(* Logix 5000 AddOnInstructionDefinition export Banner_R95C_4B4UI_Param_v4; software revision 33.00; part 2 of 2 *)
(* tags used below, declared in another part *)
   R95C : Banner_R95C_4B4UI_v4;
   Port_Data : Banner_IOL_Port_v4;
   Port : INT;   // Port Number that device is plugged into.
   Local_Control : DINT;
   Command_Being_Processed : BOOL;
   Update_Archive : BOOL;
   Index_Write_Inprocess : DINT;
   Index_Write_Control : DINT;
   Inprocess_Index : DINT;
   Index2 : DINT;
   Index3 : DINT;
(* Banner_R95C_4B4UI_Param_v4, continued *)

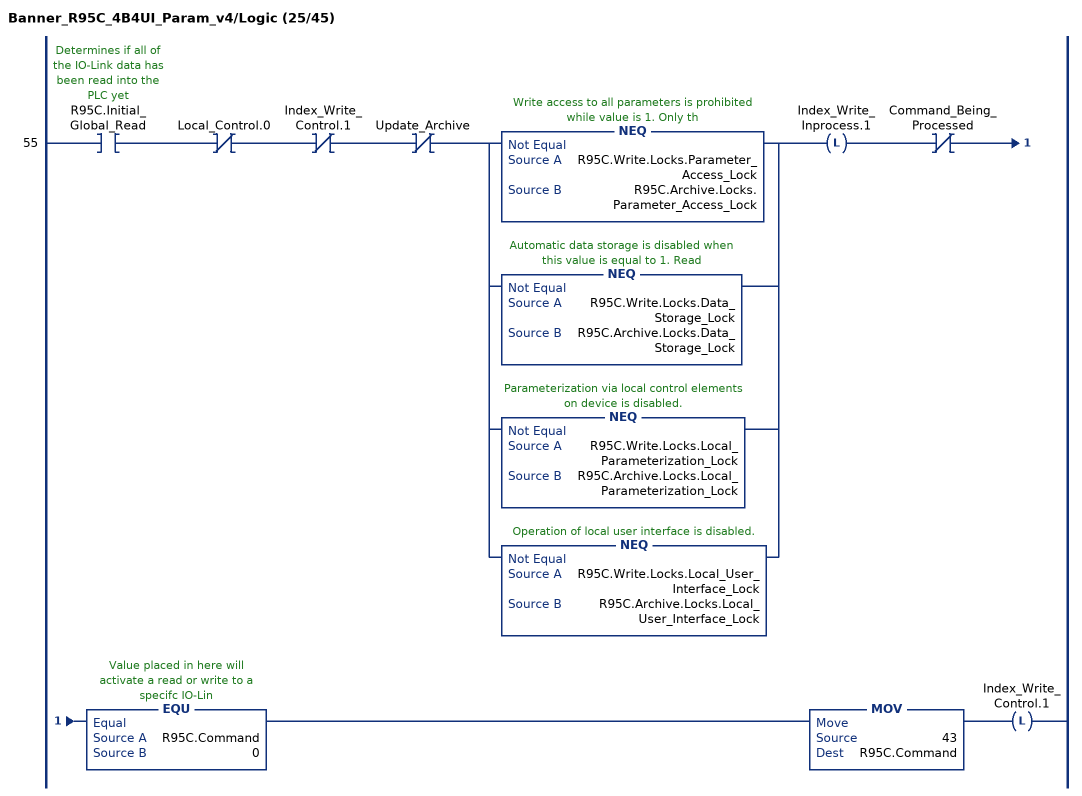
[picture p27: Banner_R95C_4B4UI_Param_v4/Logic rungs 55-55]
   55: XIC(R95C.Initial_Global_Read)XIO(Local_Control.0)XIO(Index_Write_Control.1)XIO(Update_Archive)[NEQ(R95C.Write.Locks.Parameter_Access_Lock,R95C.Archive.Locks.Parameter_Access_Lock) ,NEQ(R95C.Write.Locks.Data_Storage_Lock,R95C.Archive.Locks.Data_Storage_Lock) ,NEQ(R95C.Write.Locks.Local_Parameterization_Lock,R95C.Archive.Locks.Local_Parameterization_Lock) ,NEQ(R95C.Write.Locks.Local_User_Interface_Lock,R95C.Archive.Locks.Local_User_Interface_Lock) ]OTL(Index_Write_Inprocess.1)XIO(Command_Being_Processed)EQU(R95C.Command,0)MOV(43,R95C.Command)OTL(Index_Write_Control.1);
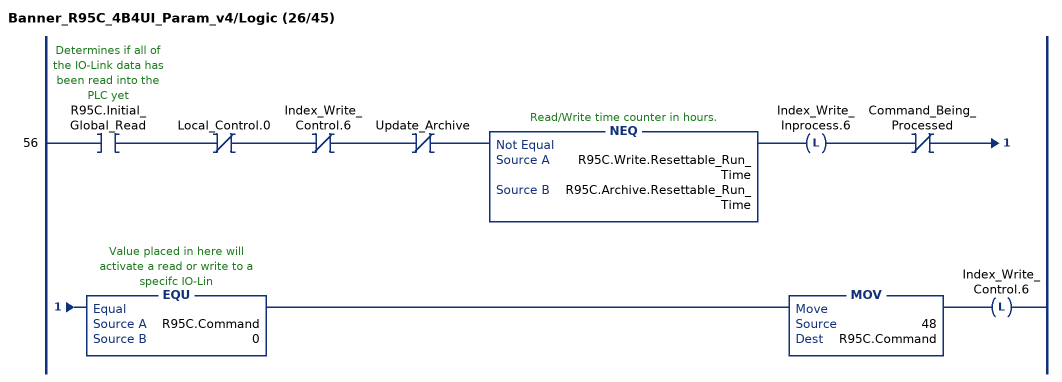
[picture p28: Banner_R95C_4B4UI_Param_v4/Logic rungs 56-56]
   56: XIC(R95C.Initial_Global_Read)XIO(Local_Control.0)XIO(Index_Write_Control.6)XIO(Update_Archive)NEQ(R95C.Write.Resettable_Run_Time,R95C.Archive.Resettable_Run_Time)OTL(Index_Write_Inprocess.6)XIO(Command_Being_Processed)EQU(R95C.Command,0)MOV(48,R95C.Command)OTL(Index_Write_Control.6);
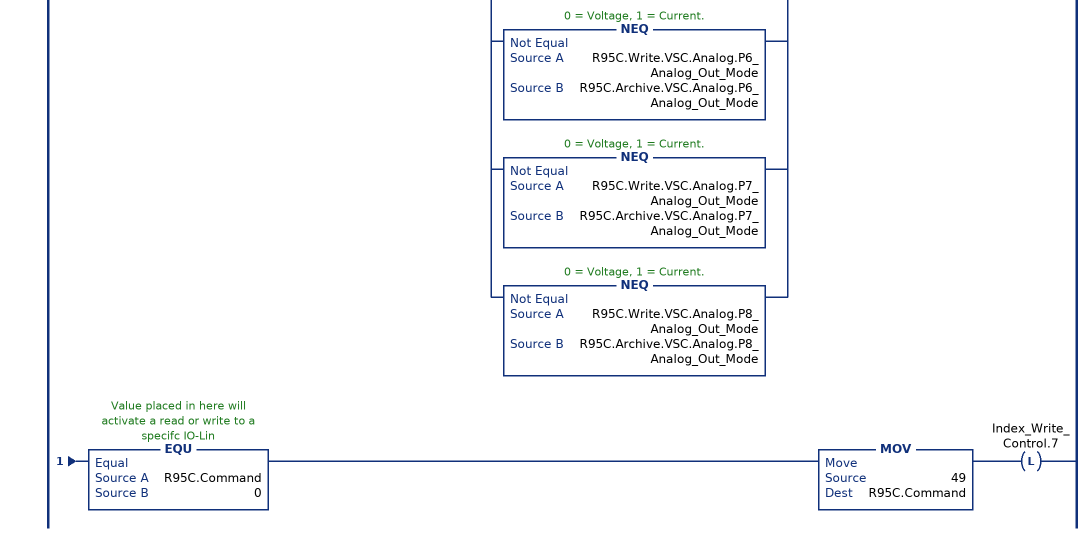
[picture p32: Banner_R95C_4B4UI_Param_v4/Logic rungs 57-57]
   57: XIC(R95C.Initial_Global_Read)XIO(Local_Control.0)XIO(Index_Write_Control.7)XIO(Update_Archive)[NEQ(R95C.Write.VSC.PDI_Config,R95C.Archive.VSC.PDI_Config) ,NEQ(R95C.Write.VSC.Measure1.Channel_Selection,R95C.Archive.VSC.Measure1.Channel_Selection) ,NEQ(R95C.Write.VSC.Measure1.Port_Selection,R95C.Archive.VSC.Measure1.Port_Selection) ,NEQ(R95C.Write.VSC.Measure1.Metric_Selection,R95C.Archive.VSC.Measure1.Metric_Selection) ,NEQ(R95C.Write.VSC.Measure2.Channel_Selection,R95C.Archive.VSC.Measure2.Channel_Selection) ,NEQ(R95C.Write.VSC.Measure2.Port_Selection,R95C.Archive.VSC.Measure2.Port_Selection) ,NEQ(R95C.Write.VSC.Measure2.Metric_Selection,R95C.Archive.VSC.Measure2.Metric_Selection) ,NEQ(R95C.Write.VSC.Measure3.Channel_Selection,R95C.Archive.VSC.Measure3.Channel_Selection) ,NEQ(R95C.Write.VSC.Measure3.Port_Selection,R95C.Archive.VSC.Measure3.Port_Selection) ,NEQ(R95C.Write.VSC.Measure3.Metric_Selection,R95C.Archive.VSC.Measure3.Metric_Selection) ,NEQ(R95C.Write.VSC.Measure4.Channel_Selection,R95C.Archive.VSC.Measure4.Channel_Selection) ,NEQ(R95C.Write.VSC.Measure4.Port_Selection,R95C.Archive.VSC.Measure4.Port_Selection) ,NEQ(R95C.Write.VSC.Measure4.Metric_Selection,R95C.Archive.VSC.Measure4.Metric_Selection) ,NEQ(R95C.Write.VSC.POVR.PDO5_OVD,R95C.Archive.VSC.POVR.PDO5_OVD) ,NEQ(R95C.Write.VSC.POVR.PDO6_OVD,R95C.Archive.VSC.POVR.PDO6_OVD) ,NEQ(R95C.Write.VSC.POVR.PDO7_OVD,R95C.Archive.VSC.POVR.PDO7_OVD) ,NEQ(R95C.Write.VSC.POVR.PDO8_OVD,R95C.Archive.VSC.POVR.PDO8_OVD) ,NEQ(R95C.Write.VSC.IOL_Filter_Time,R95C.Archive.VSC.IOL_Filter_Time) ,NEQ(R95C.Write.VSC.Analog.P5_Mode_Analog_In,R95C.Archive.VSC.Analog.P5_Mode_Analog_In) ,NEQ(R95C.Write.VSC.Analog.P6_Mode_Analog_In,R95C.Archive.VSC.Analog.P6_Mode_Analog_In) ,NEQ(R95C.Write.VSC.Analog.P7_Mode_Analog_In,R95C.Archive.VSC.Analog.P7_Mode_Analog_In) ,NEQ(R95C.Write.VSC.Analog.P8_Mode_Analog_In,R95C.Archive.VSC.Analog.P8_Mode_Analog_In) ,NEQ(R95C.Write.VSC.Analog.P5_Analog_Out_Mode,R95C.Archive.VSC.Analog.P5_Analog_Out_Mode) ,NEQ(R95C.Write.VSC.Analog.P6_Analog_Out_Mode,R95C.Archive.VSC.Analog.P6_Analog_Out_Mode) ,NEQ(R95C.Write.VSC.Analog.P7_Analog_Out_Mode,R95C.Archive.VSC.Analog.P7_Analog_Out_Mode) ,NEQ(R95C.Write.VSC.Analog.P8_Analog_Out_Mode,R95C.Archive.VSC.Analog.P8_Analog_Out_Mode) ]OTL(Index_Write_Inprocess.7)XIO(Command_Being_Processed)EQU(R95C.Command,0)MOV(49,R95C.Command)OTL(Index_Write_Control.7);
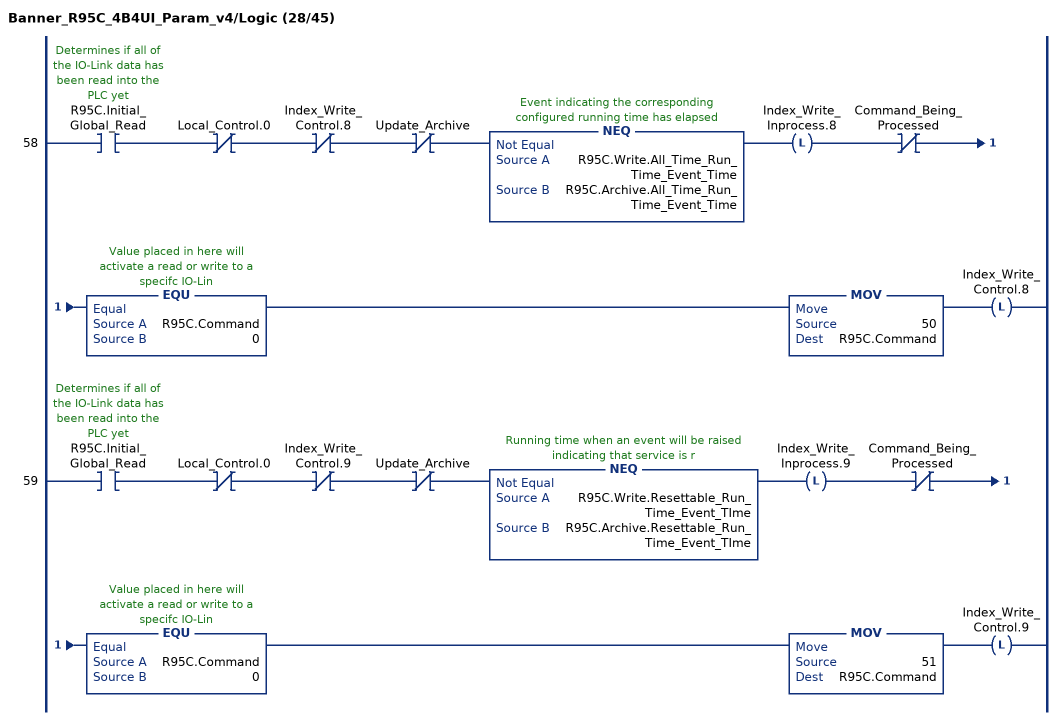
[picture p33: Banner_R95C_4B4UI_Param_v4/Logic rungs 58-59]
   58: XIC(R95C.Initial_Global_Read)XIO(Local_Control.0)XIO(Index_Write_Control.8)XIO(Update_Archive)NEQ(R95C.Write.All_Time_Run_Time_Event_Time,R95C.Archive.All_Time_Run_Time_Event_Time)OTL(Index_Write_Inprocess.8)XIO(Command_Being_Processed)EQU(R95C.Command,0)MOV(50,R95C.Command)OTL(Index_Write_Control.8);
   59: XIC(R95C.Initial_Global_Read)XIO(Local_Control.0)XIO(Index_Write_Control.9)XIO(Update_Archive)NEQ(R95C.Write.Resettable_Run_Time_Event_TIme,R95C.Archive.Resettable_Run_Time_Event_TIme)OTL(Index_Write_Inprocess.9)XIO(Command_Being_Processed)EQU(R95C.Command,0)MOV(51,R95C.Command)OTL(Index_Write_Control.9);
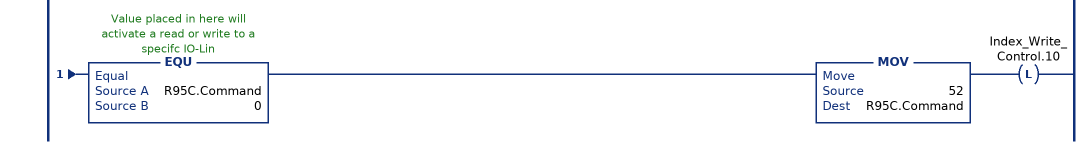
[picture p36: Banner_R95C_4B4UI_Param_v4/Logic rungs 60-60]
   60: XIC(R95C.Initial_Global_Read)XIO(Local_Control.0)XIO(Index_Write_Control.10)XIO(Update_Archive)[NEQ(R95C.Write.SMR.P4_D2_Reset_Count,R95C.Archive.SMR.P4_D2_Reset_Count) ,NEQ(R95C.Write.SMR.P4_D1_Reset_Count,R95C.Archive.SMR.P4_D1_Reset_Count) ,NEQ(R95C.Write.SMR.P3_D2_Reset_Count,R95C.Archive.SMR.P3_D2_Reset_Count) ,NEQ(R95C.Write.SMR.P3_D1_Reset_Count,R95C.Archive.SMR.P3_D1_Reset_Count) ,NEQ(R95C.Write.SMR.P2_D2_Reset_Count,R95C.Archive.SMR.P2_D2_Reset_Count) ,NEQ(R95C.Write.SMR.P2_D1_Reset_Count,R95C.Archive.SMR.P2_D1_Reset_Count) ,NEQ(R95C.Write.SMR.P1_D2_Reset_Count,R95C.Archive.SMR.P1_D2_Reset_Count) ,NEQ(R95C.Write.SMR.P1_D1_Reset_Count,R95C.Archive.SMR.P1_D1_Reset_Count) ,NEQ(R95C.Write.SMR.P1_Discrete1,R95C.Archive.SMR.P1_Discrete1) ,NEQ(R95C.Write.SMR.P1_Discrete2,R95C.Archive.SMR.P1_Discrete2) ,NEQ(R95C.Write.SMR.P2_Discrete1,R95C.Archive.SMR.P2_Discrete1) ,NEQ(R95C.Write.SMR.P2_Discrete2,R95C.Archive.SMR.P2_Discrete2) ,NEQ(R95C.Write.SMR.P3_Discrete1,R95C.Archive.SMR.P3_Discrete1) ,NEQ(R95C.Write.SMR.P3_Discrete2,R95C.Archive.SMR.P3_Discrete2) ,NEQ(R95C.Write.SMR.P4_Discrete1,R95C.Archive.SMR.P4_Discrete1) ,NEQ(R95C.Write.SMR.P4_Discrete2,R95C.Archive.SMR.P4_Discrete2) ]OTL(Index_Write_Inprocess.10)XIO(Command_Being_Processed)EQU(R95C.Command,0)MOV(52,R95C.Command)OTL(Index_Write_Control.10);
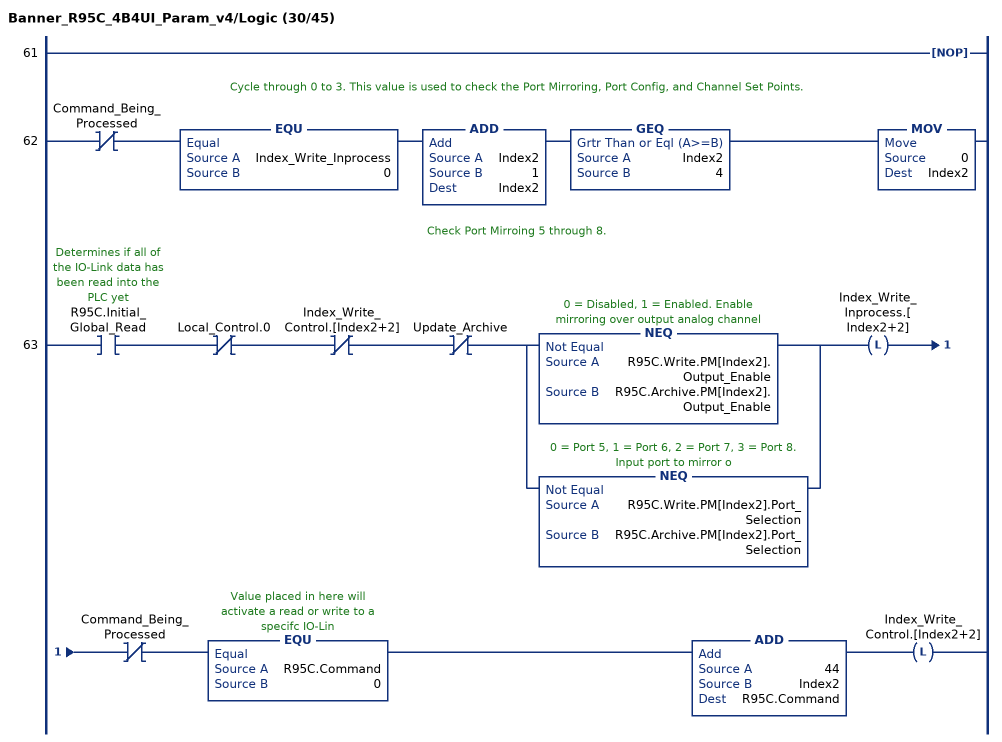
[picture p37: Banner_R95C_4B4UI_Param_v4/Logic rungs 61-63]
   61: NOP();
   // Cycle through 0 to 3. This value is used to check the Port Mirroring, Port Config, and Channel Set Points.
   62: XIO(Command_Being_Processed)EQU(Index_Write_Inprocess,0)ADD(Index2,1,Index2)GEQ(Index2,4)MOV(0,Index2);
   // Check Port Mirroing 5 through 8.
   63: XIC(R95C.Initial_Global_Read)XIO(Local_Control.0)XIO(Index_Write_Control.[Index2+2])XIO(Update_Archive)[NEQ(R95C.Write.PM[Index2].Output_Enable,R95C.Archive.PM[Index2].Output_Enable) ,NEQ(R95C.Write.PM[Index2].Port_Selection,R95C.Archive.PM[Index2].Port_Selection) ]OTL(Index_Write_Inprocess.[Index2+2])XIO(Command_Being_Processed)EQU(R95C.Command,0)ADD(44,Index2,R95C.Command)OTL(Index_Write_Control.[Index2+2]);
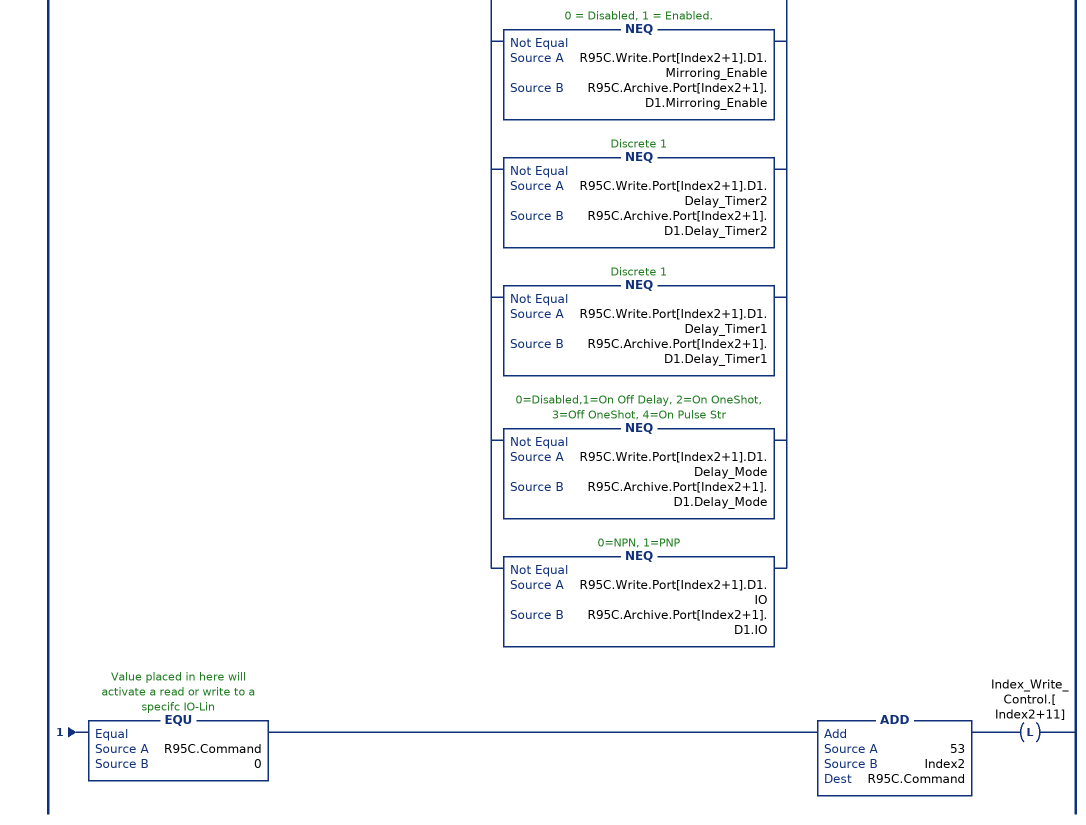
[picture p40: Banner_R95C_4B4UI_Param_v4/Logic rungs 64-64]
   // Check Port Confiuration 1 through 4.
   64: XIC(R95C.Initial_Global_Read)XIO(Local_Control.0)XIO(Index_Write_Control.[Index2+11])XIO(Update_Archive)[NEQ(R95C.Write.Port[Index2+1].D2.PFM_Far_Freq,R95C.Archive.Port[Index2+1].D2.PFM_Far_Freq) ,NEQ(R95C.Write.Port[Index2+1].D2.PFM_Near_Freq,R95C.Archive.Port[Index2+1].D2.PFM_Near_Freq) ,NEQ(R95C.Write.Port[Index2+1].D2.Mirroring_Inversion,R95C.Archive.Port[Index2+1].D2.Mirroring_Inversion) ,NEQ(R95C.Write.Port[Index2+1].D2.Mirroring_Channel_Selection,R95C.Archive.Port[Index2+1].D2.Mirroring_Channel_Selection) ,NEQ(R95C.Write.Port[Index2+1].D2.Mirroring_Port_Selection,R95C.Archive.Port[Index2+1].D2.Mirroring_Port_Selection) ,NEQ(R95C.Write.Port[Index2+1].D2.Mirroring_Enable,R95C.Archive.Port[Index2+1].D2.Mirroring_Enable) ,NEQ(R95C.Write.Port[Index2+1].D2.Delay_Timer2,R95C.Archive.Port[Index2+1].D2.Delay_Timer2) ,NEQ(R95C.Write.Port[Index2+1].D2.Delay_Timer1,R95C.Archive.Port[Index2+1].D2.Delay_Timer1) ,NEQ(R95C.Write.Port[Index2+1].D2.Delay_Mode,R95C.Archive.Port[Index2+1].D2.Delay_Mode) ,NEQ(R95C.Write.Port[Index2+1].D2.IO,R95C.Archive.Port[Index2+1].D2.IO) ,NEQ(R95C.Write.Port[Index2+1].D1.PFM_Far_Freq,R95C.Archive.Port[Index2+1].D1.PFM_Far_Freq) ,NEQ(R95C.Write.Port[Index2+1].D1.PFM_Near_Freq,R95C.Archive.Port[Index2+1].D1.PFM_Near_Freq) ,NEQ(R95C.Write.Port[Index2+1].D1.Mirroring_Inversion,R95C.Archive.Port[Index2+1].D1.Mirroring_Inversion) ,NEQ(R95C.Write.Port[Index2+1].D1.Mirroring_Channel_Selection,R95C.Archive.Port[Index2+1].D1.Mirroring_Channel_Selection) ,NEQ(R95C.Write.Port[Index2+1].D1.Mirroring_Port_Selection,R95C.Archive.Port[Index2+1].D1.Mirroring_Port_Selection) ,NEQ(R95C.Write.Port[Index2+1].D1.Mirroring_Enable,R95C.Archive.Port[Index2+1].D1.Mirroring_Enable) ,NEQ(R95C.Write.Port[Index2+1].D1.Delay_Timer2,R95C.Archive.Port[Index2+1].D1.Delay_Timer2) ,NEQ(R95C.Write.Port[Index2+1].D1.Delay_Timer1,R95C.Archive.Port[Index2+1].D1.Delay_Timer1) ,NEQ(R95C.Write.Port[Index2+1].D1.Delay_Mode,R95C.Archive.Port[Index2+1].D1.Delay_Mode) ,NEQ(R95C.Write.Port[Index2+1].D1.IO,R95C.Archive.Port[Index2+1].D1.IO) ]OTL(Index_Write_Inprocess.[Index2+11])XIO(Command_Being_Processed)EQU(R95C.Command,0)ADD(53,Index2,R95C.Command)OTL(Index_Write_Control.[Index2+11]);
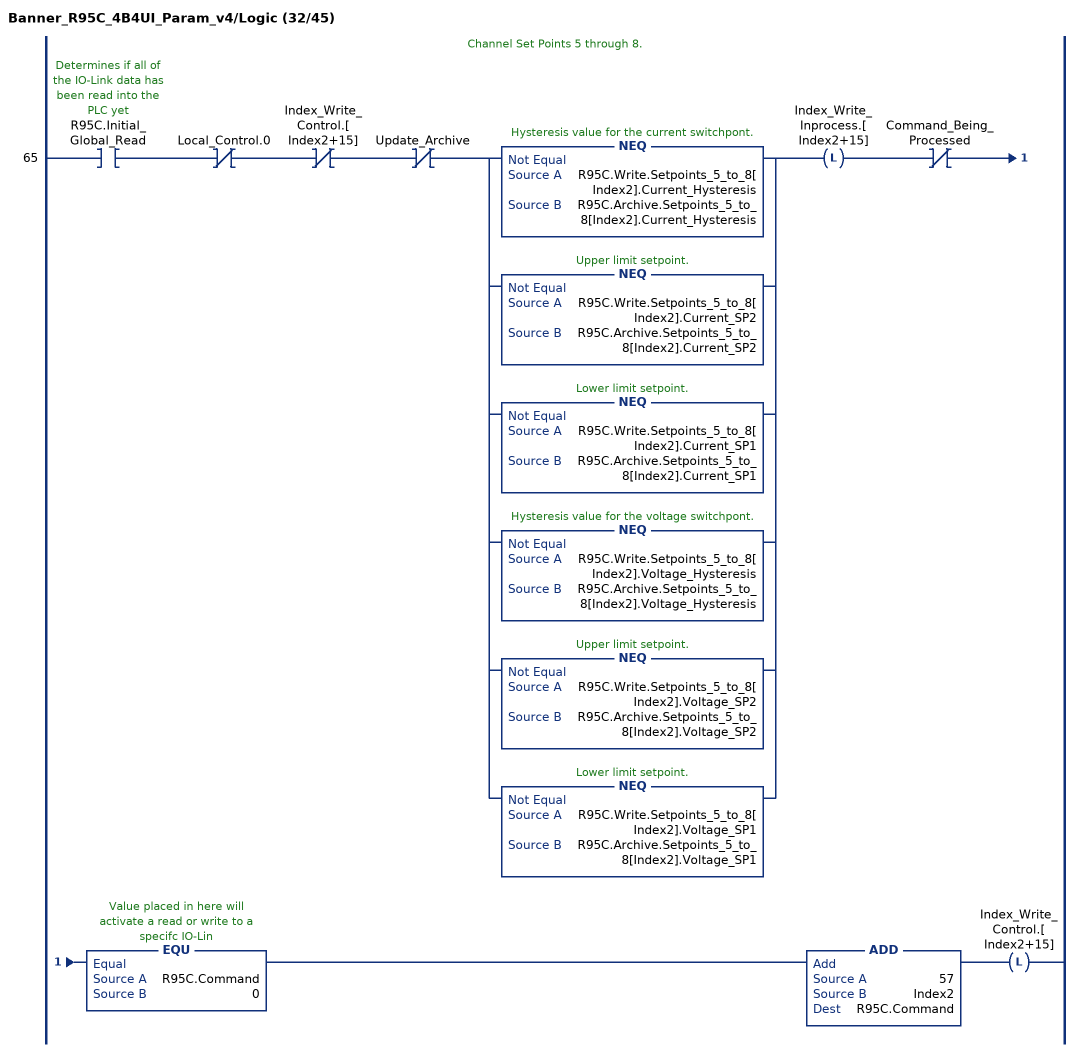
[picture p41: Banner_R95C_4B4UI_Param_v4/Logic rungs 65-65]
   // Channel Set Points 5 through 8.
   65: XIC(R95C.Initial_Global_Read)XIO(Local_Control.0)XIO(Index_Write_Control.[Index2+15])XIO(Update_Archive)[NEQ(R95C.Write.Setpoints_5_to_8[Index2].Current_Hysteresis,R95C.Archive.Setpoints_5_to_8[Index2].Current_Hysteresis) ,NEQ(R95C.Write.Setpoints_5_to_8[Index2].Current_SP2,R95C.Archive.Setpoints_5_to_8[Index2].Current_SP2) ,NEQ(R95C.Write.Setpoints_5_to_8[Index2].Current_SP1,R95C.Archive.Setpoints_5_to_8[Index2].Current_SP1) ,NEQ(R95C.Write.Setpoints_5_to_8[Index2].Voltage_Hysteresis,R95C.Archive.Setpoints_5_to_8[Index2].Voltage_Hysteresis) ,NEQ(R95C.Write.Setpoints_5_to_8[Index2].Voltage_SP2,R95C.Archive.Setpoints_5_to_8[Index2].Voltage_SP2) ,NEQ(R95C.Write.Setpoints_5_to_8[Index2].Voltage_SP1,R95C.Archive.Setpoints_5_to_8[Index2].Voltage_SP1) ]OTL(Index_Write_Inprocess.[Index2+15])XIO(Command_Being_Processed)EQU(R95C.Command,0)ADD(57,Index2,R95C.Command)OTL(Index_Write_Control.[Index2+15]);
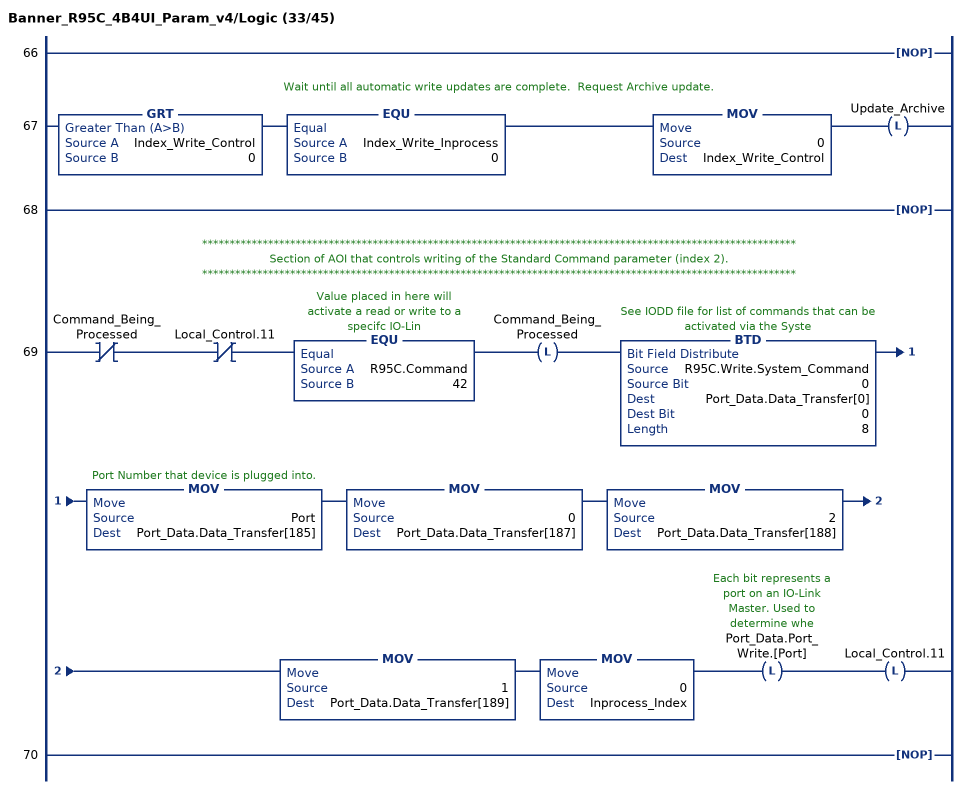
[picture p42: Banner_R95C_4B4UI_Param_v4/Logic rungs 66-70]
   66: NOP();
   // Wait until all automatic write updates are complete.  Request Archive update.
   67: GRT(Index_Write_Control,0)EQU(Index_Write_Inprocess,0)MOV(0,Index_Write_Control)OTL(Update_Archive);
   68: NOP();
   // ************************************************************************************************************
   // Section of AOI that controls writing of the Standard Command parameter (index 2).
   // ************************************************************************************************************
   69: XIO(Command_Being_Processed)XIO(Local_Control.11)EQU(R95C.Command,42)OTL(Command_Being_Processed)BTD(R95C.Write.System_Command,0,Port_Data.Data_Transfer[0],0,8)MOV(Port,Port_Data.Data_Transfer[185])MOV(0,Port_Data.Data_Transfer[187])MOV(2,Port_Data.Data_Transfer[188])MOV(1,Port_Data.Data_Transfer[189])MOV(0,Inprocess_Index)OTL(Port_Data.Port_Write.[Port])OTL(Local_Control.11);
   70: NOP();
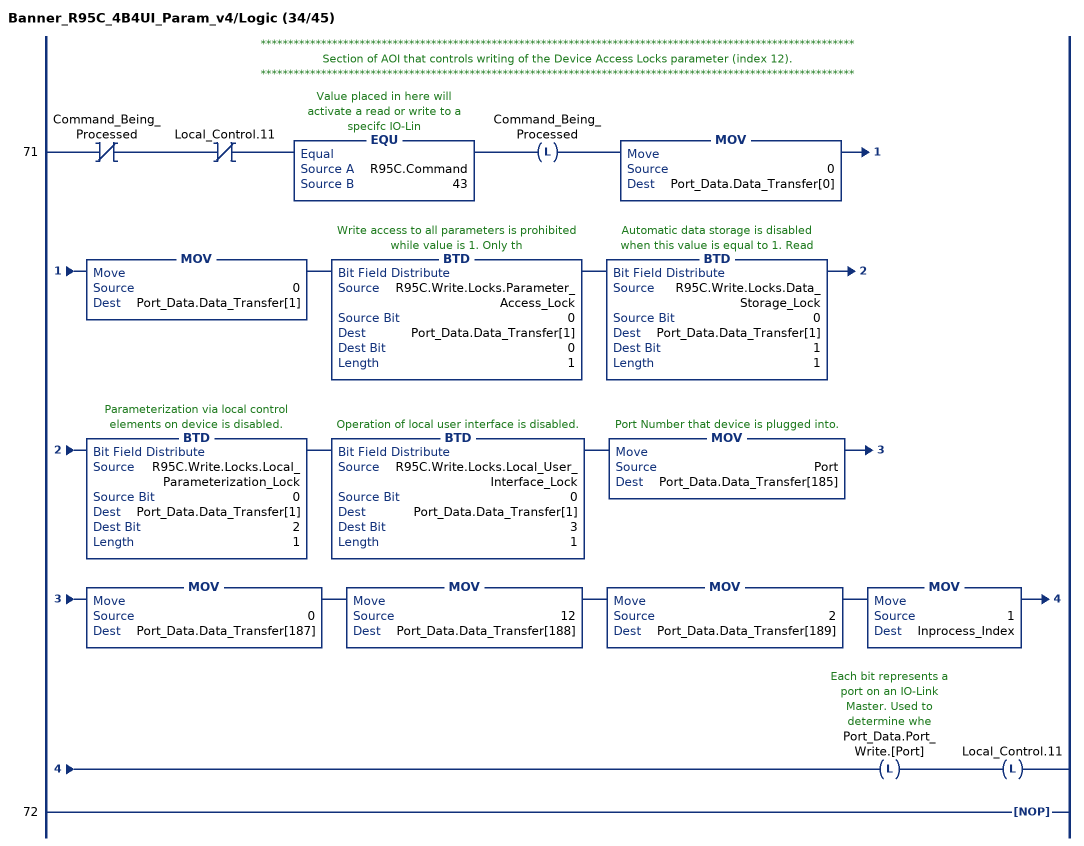
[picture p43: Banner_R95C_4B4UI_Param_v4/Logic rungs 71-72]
   // ************************************************************************************************************
   // Section of AOI that controls writing of the Device Access Locks parameter (index 12).
   // ************************************************************************************************************
   71: XIO(Command_Being_Processed)XIO(Local_Control.11)EQU(R95C.Command,43)OTL(Command_Being_Processed)MOV(0,Port_Data.Data_Transfer[0])MOV(0,Port_Data.Data_Transfer[1])BTD(R95C.Write.Locks.Parameter_Access_Lock,0,Port_Data.Data_Transfer[1],0,1)BTD(R95C.Write.Locks.Data_Storage_Lock,0,Port_Data.Data_Transfer[1],1,1)BTD(R95C.Write.Locks.Local_Parameterization_Lock,0,Port_Data.Data_Transfer[1],2,1)BTD(R95C.Write.Locks.Local_User_Interface_Lock,0,Port_Data.Data_Transfer[1],3,1)MOV(Port,Port_Data.Data_Transfer[185])MOV(0,Port_Data.Data_Transfer[187])MOV(12,Port_Data.Data_Transfer[188])MOV(2,Port_Data.Data_Transfer[189])MOV(1,Inprocess_Index)OTL(Port_Data.Port_Write.[Port])OTL(Local_Control.11);
   72: NOP();
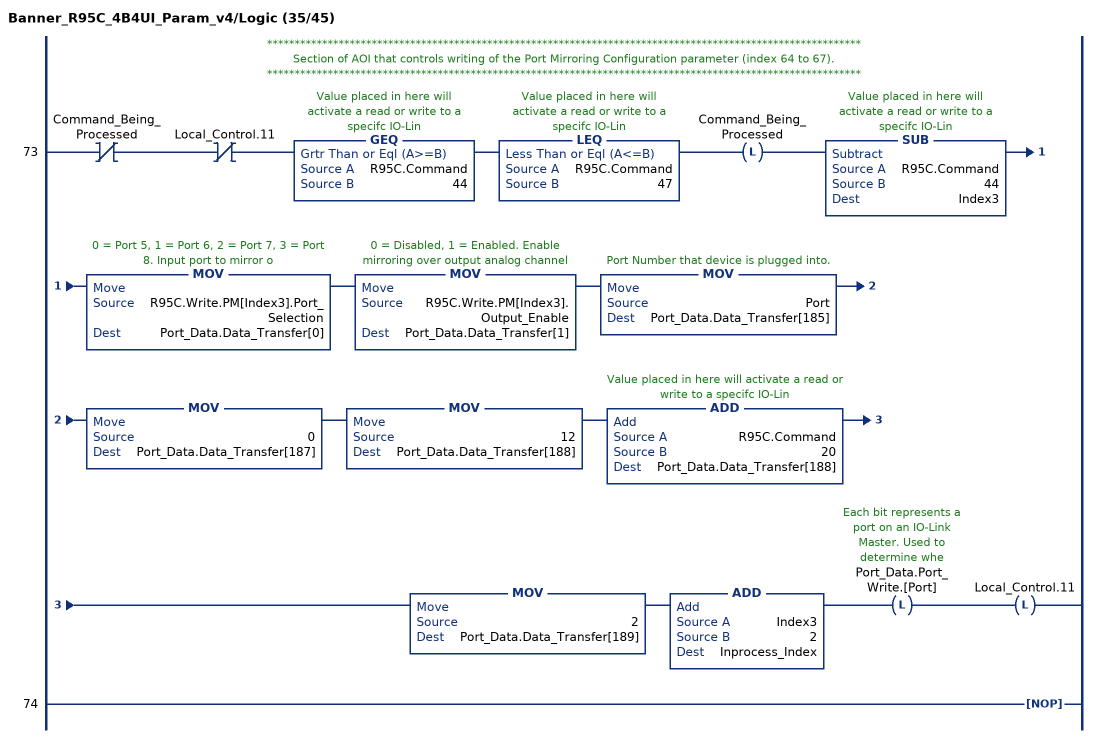
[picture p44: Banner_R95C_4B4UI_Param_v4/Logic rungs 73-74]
   // ************************************************************************************************************
   // Section of AOI that controls writing of the Port Mirroring Configuration parameter (index 64 to 67).
   // ************************************************************************************************************
   73: XIO(Command_Being_Processed)XIO(Local_Control.11)GEQ(R95C.Command,44)LEQ(R95C.Command,47)OTL(Command_Being_Processed)SUB(R95C.Command,44,Index3)MOV(R95C.Write.PM[Index3].Port_Selection,Port_Data.Data_Transfer[0])MOV(R95C.Write.PM[Index3].Output_Enable,Port_Data.Data_Transfer[1])MOV(Port,Port_Data.Data_Transfer[185])MOV(0,Port_Data.Data_Transfer[187])MOV(12,Port_Data.Data_Transfer[188])ADD(R95C.Command,20,Port_Data.Data_Transfer[188])MOV(2,Port_Data.Data_Transfer[189])ADD(Index3,2,Inprocess_Index)OTL(Port_Data.Port_Write.[Port])OTL(Local_Control.11);
   74: NOP();
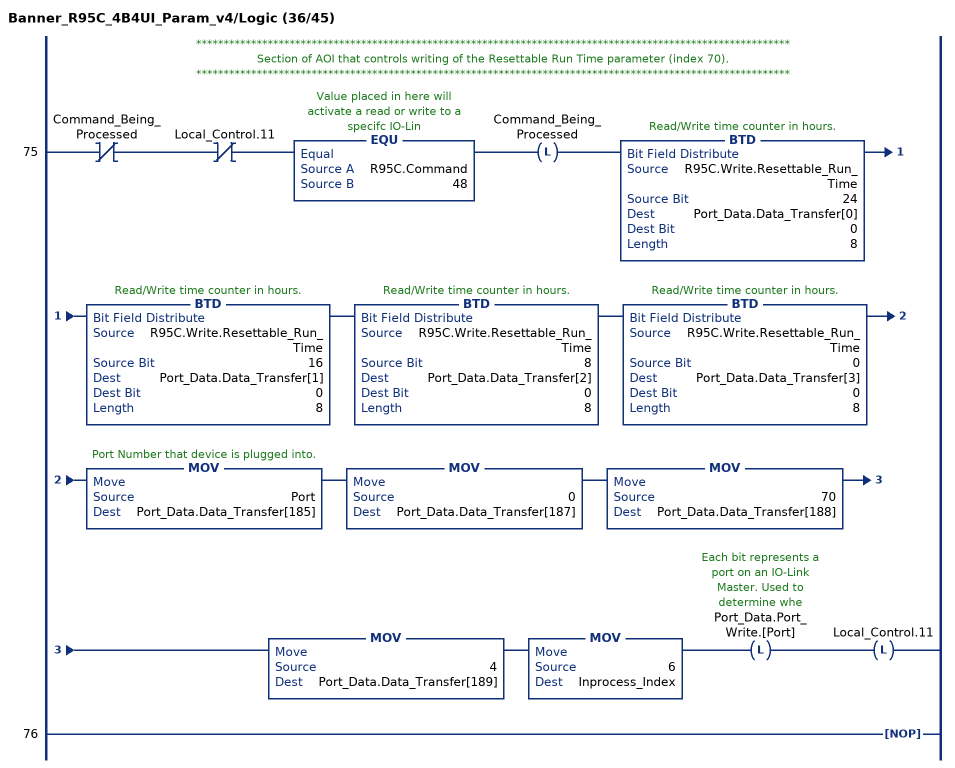
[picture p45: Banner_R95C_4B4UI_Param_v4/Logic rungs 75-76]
   // ************************************************************************************************************
   // Section of AOI that controls writing of the Resettable Run Time parameter (index 70).
   // ************************************************************************************************************
   75: XIO(Command_Being_Processed)XIO(Local_Control.11)EQU(R95C.Command,48)OTL(Command_Being_Processed)BTD(R95C.Write.Resettable_Run_Time,24,Port_Data.Data_Transfer[0],0,8)BTD(R95C.Write.Resettable_Run_Time,16,Port_Data.Data_Transfer[1],0,8)BTD(R95C.Write.Resettable_Run_Time,8,Port_Data.Data_Transfer[2],0,8)BTD(R95C.Write.Resettable_Run_Time,0,Port_Data.Data_Transfer[3],0,8)MOV(Port,Port_Data.Data_Transfer[185])MOV(0,Port_Data.Data_Transfer[187])MOV(70,Port_Data.Data_Transfer[188])MOV(4,Port_Data.Data_Transfer[189])MOV(6,Inprocess_Index)OTL(Port_Data.Port_Write.[Port])OTL(Local_Control.11);
   76: NOP();
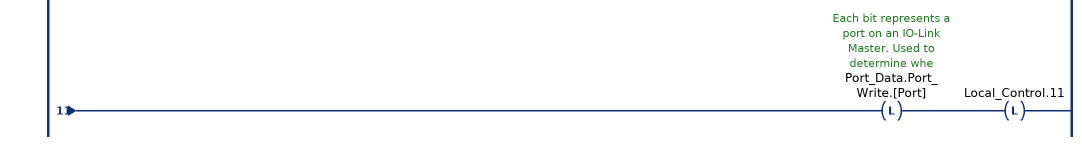
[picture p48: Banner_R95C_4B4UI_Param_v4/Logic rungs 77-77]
   // ************************************************************************************************************
   // Section of AOI that controls writing of the Vendor Specific Configuration parameter (index 76).
   // ************************************************************************************************************
   77: XIO(Command_Being_Processed)XIO(Local_Control.11)EQU(R95C.Command,49)OTL(Command_Being_Processed)BTD(R95C.Write.VSC.Analog.P8_Analog_Out_Mode,0,Port_Data.Data_Transfer[0],0,8)BTD(R95C.Write.VSC.Analog.P7_Analog_Out_Mode,0,Port_Data.Data_Transfer[1],0,8)BTD(R95C.Write.VSC.Analog.P6_Analog_Out_Mode,0,Port_Data.Data_Transfer[2],0,8)BTD(R95C.Write.VSC.Analog.P5_Analog_Out_Mode,0,Port_Data.Data_Transfer[3],0,8)BTD(R95C.Write.VSC.Analog.P8_Mode_Analog_In,0,Port_Data.Data_Transfer[4],0,8)BTD(R95C.Write.VSC.Analog.P7_Mode_Analog_In,0,Port_Data.Data_Transfer[5],0,8)BTD(R95C.Write.VSC.Analog.P6_Mode_Analog_In,0,Port_Data.Data_Transfer[6],0,8)BTD(R95C.Write.VSC.Analog.P5_Mode_Analog_In,0,Port_Data.Data_Transfer[7],0,8)BTD(R95C.Write.VSC.IOL_Filter_Time,8,Port_Data.Data_Transfer[8],0,8)BTD(R95C.Write.VSC.IOL_Filter_Time,0,Port_Data.Data_Transfer[9],0,8)BTD(R95C.Write.VSC.POVR.PDO8_OVD,0,Port_Data.Data_Transfer[10],0,8)BTD(R95C.Write.VSC.POVR.PDO7_OVD,0,Port_Data.Data_Transfer[11],0,8)BTD(R95C.Write.VSC.POVR.PDO6_OVD,0,Port_Data.Data_Transfer[12],0,8)BTD(R95C.Write.VSC.POVR.PDO5_OVD,0,Port_Data.Data_Transfer[13],0,8)BTD(R95C.Write.VSC.Measure4.Channel_Selection,0,Port_Data.Data_Transfer[14],0,8)BTD(R95C.Write.VSC.Measure4.Port_Selection,0,Port_Data.Data_Transfer[15],0,8)BTD(R95C.Write.VSC.Measure4.Metric_Selection,0,Port_Data.Data_Transfer[16],0,8)BTD(R95C.Write.VSC.Measure3.Channel_Selection,0,Port_Data.Data_Transfer[17],0,8)BTD(R95C.Write.VSC.Measure3.Port_Selection,0,Port_Data.Data_Transfer[18],0,8)BTD(R95C.Write.VSC.Measure3.Metric_Selection,0,Port_Data.Data_Transfer[19],0,8)BTD(R95C.Write.VSC.Measure2.Channel_Selection,0,Port_Data.Data_Transfer[20],0,8)BTD(R95C.Write.VSC.Measure2.Port_Selection,0,Port_Data.Data_Transfer[21],0,8)BTD(R95C.Write.VSC.Measure2.Metric_Selection,0,Port_Data.Data_Transfer[22],0,8)BTD(R95C.Write.VSC.Measure1.Channel_Selection,0,Port_Data.Data_Transfer[23],0,8)BTD(R95C.Write.VSC.Measure1.Port_Selection,0,Port_Data.Data_Transfer[24],0,8)BTD(R95C.Write.VSC.Measure1.Metric_Selection,0,Port_Data.Data_Transfer[25],0,8)BTD(R95C.Write.VSC.PDI_Config,0,Port_Data.Data_Transfer[26],0,8)MOV(Port,Port_Data.Data_Transfer[185])MOV(0,Port_Data.Data_Transfer[187])MOV(76,Port_Data.Data_Transfer[188])MOV(27,Port_Data.Data_Transfer[189])MOV(7,Inprocess_Index)OTL(Port_Data.Port_Write.[Port])OTL(Local_Control.11);
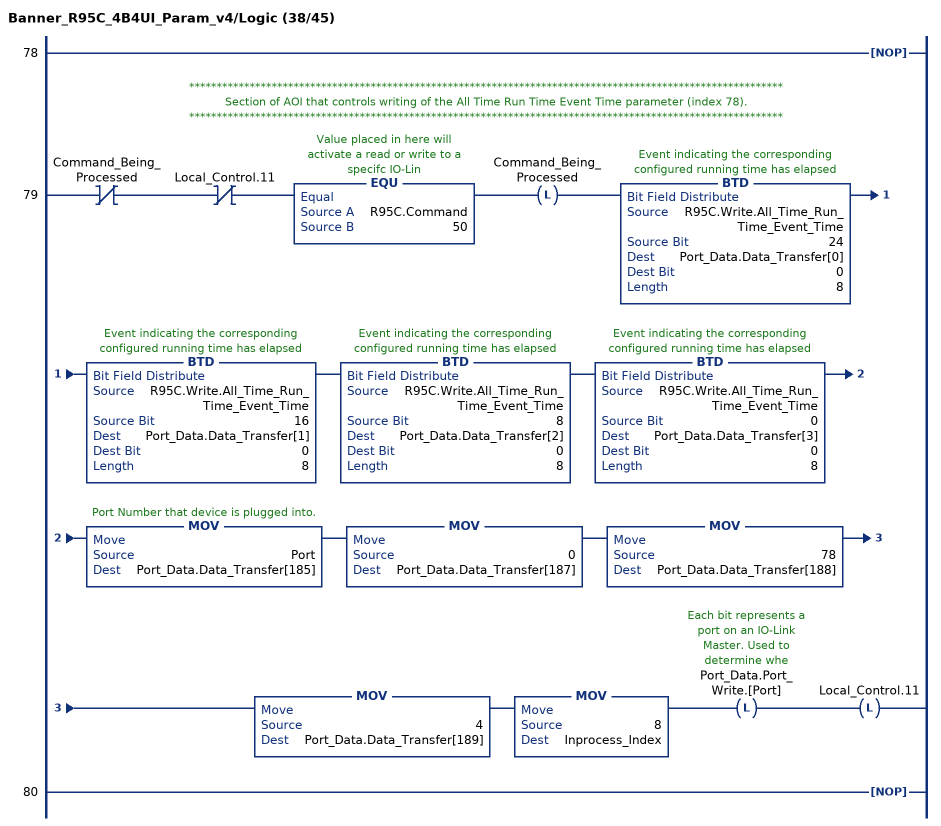
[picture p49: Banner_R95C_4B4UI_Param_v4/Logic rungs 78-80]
   78: NOP();
   // ************************************************************************************************************
   // Section of AOI that controls writing of the All Time Run Time Event Time parameter (index 78).
   // ************************************************************************************************************
   79: XIO(Command_Being_Processed)XIO(Local_Control.11)EQU(R95C.Command,50)OTL(Command_Being_Processed)BTD(R95C.Write.All_Time_Run_Time_Event_Time,24,Port_Data.Data_Transfer[0],0,8)BTD(R95C.Write.All_Time_Run_Time_Event_Time,16,Port_Data.Data_Transfer[1],0,8)BTD(R95C.Write.All_Time_Run_Time_Event_Time,8,Port_Data.Data_Transfer[2],0,8)BTD(R95C.Write.All_Time_Run_Time_Event_Time,0,Port_Data.Data_Transfer[3],0,8)MOV(Port,Port_Data.Data_Transfer[185])MOV(0,Port_Data.Data_Transfer[187])MOV(78,Port_Data.Data_Transfer[188])MOV(4,Port_Data.Data_Transfer[189])MOV(8,Inprocess_Index)OTL(Port_Data.Port_Write.[Port])OTL(Local_Control.11);
   80: NOP();
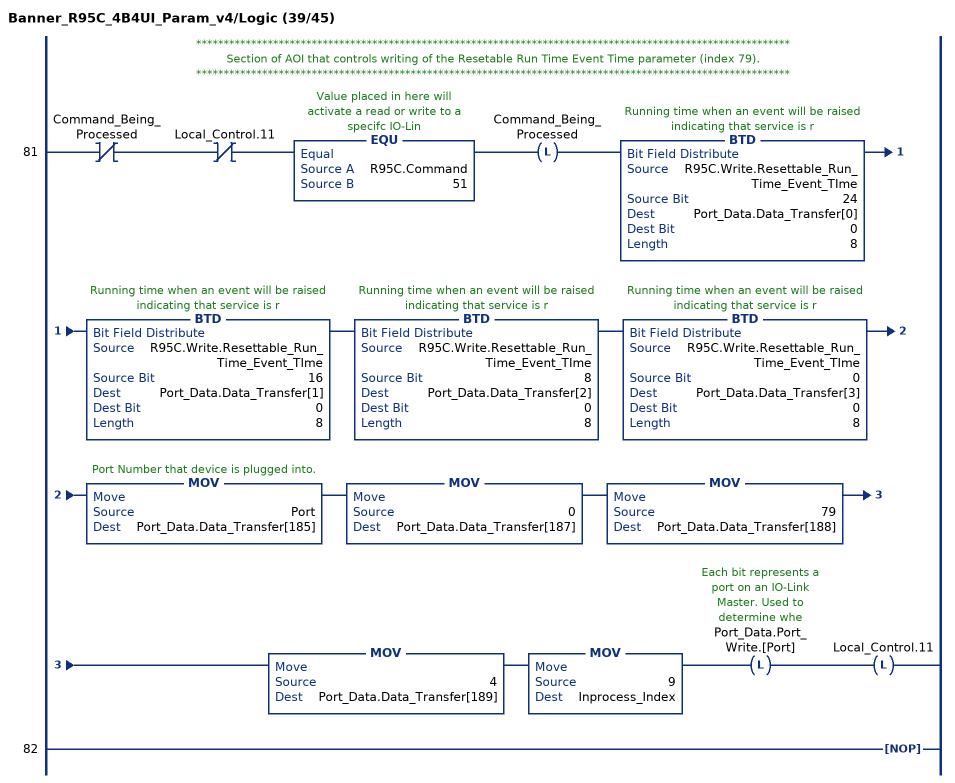
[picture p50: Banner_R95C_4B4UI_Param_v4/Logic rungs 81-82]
   // ************************************************************************************************************
   // Section of AOI that controls writing of the Resetable Run Time Event Time parameter (index 79).
   // ************************************************************************************************************
   81: XIO(Command_Being_Processed)XIO(Local_Control.11)EQU(R95C.Command,51)OTL(Command_Being_Processed)BTD(R95C.Write.Resettable_Run_Time_Event_TIme,24,Port_Data.Data_Transfer[0],0,8)BTD(R95C.Write.Resettable_Run_Time_Event_TIme,16,Port_Data.Data_Transfer[1],0,8)BTD(R95C.Write.Resettable_Run_Time_Event_TIme,8,Port_Data.Data_Transfer[2],0,8)BTD(R95C.Write.Resettable_Run_Time_Event_TIme,0,Port_Data.Data_Transfer[3],0,8)MOV(Port,Port_Data.Data_Transfer[185])MOV(0,Port_Data.Data_Transfer[187])MOV(79,Port_Data.Data_Transfer[188])MOV(4,Port_Data.Data_Transfer[189])MOV(9,Inprocess_Index)OTL(Port_Data.Port_Write.[Port])OTL(Local_Control.11);
   82: NOP();
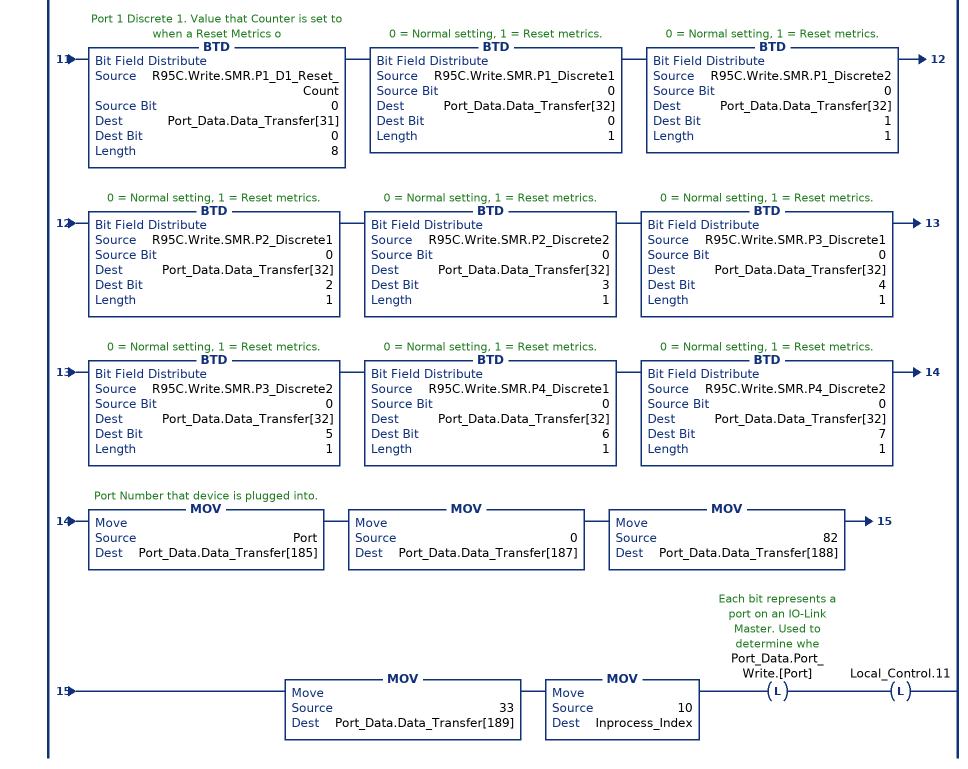
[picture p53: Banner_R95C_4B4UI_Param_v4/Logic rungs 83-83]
   // ************************************************************************************************************
   // Section of AOI that controls writing of the Selectable Metric Reset parameter (index 82).
   // ************************************************************************************************************
   83: XIO(Command_Being_Processed)XIO(Local_Control.11)EQU(R95C.Command,52)OTL(Command_Being_Processed)BTD(R95C.Write.SMR.P4_D2_Reset_Count,24,Port_Data.Data_Transfer[0],0,8)BTD(R95C.Write.SMR.P4_D2_Reset_Count,16,Port_Data.Data_Transfer[1],0,8)BTD(R95C.Write.SMR.P4_D2_Reset_Count,8,Port_Data.Data_Transfer[2],0,8)BTD(R95C.Write.SMR.P4_D2_Reset_Count,0,Port_Data.Data_Transfer[3],0,8)BTD(R95C.Write.SMR.P4_D1_Reset_Count,24,Port_Data.Data_Transfer[4],0,8)BTD(R95C.Write.SMR.P4_D1_Reset_Count,16,Port_Data.Data_Transfer[5],0,8)BTD(R95C.Write.SMR.P4_D1_Reset_Count,8,Port_Data.Data_Transfer[6],0,8)BTD(R95C.Write.SMR.P4_D1_Reset_Count,0,Port_Data.Data_Transfer[7],0,8)BTD(R95C.Write.SMR.P3_D2_Reset_Count,24,Port_Data.Data_Transfer[8],0,8)BTD(R95C.Write.SMR.P3_D2_Reset_Count,16,Port_Data.Data_Transfer[9],0,8)BTD(R95C.Write.SMR.P3_D2_Reset_Count,8,Port_Data.Data_Transfer[10],0,8)BTD(R95C.Write.SMR.P3_D2_Reset_Count,0,Port_Data.Data_Transfer[11],0,8)BTD(R95C.Write.SMR.P3_D1_Reset_Count,24,Port_Data.Data_Transfer[12],0,8)BTD(R95C.Write.SMR.P3_D1_Reset_Count,16,Port_Data.Data_Transfer[13],0,8)BTD(R95C.Write.SMR.P3_D1_Reset_Count,8,Port_Data.Data_Transfer[14],0,8)BTD(R95C.Write.SMR.P3_D1_Reset_Count,0,Port_Data.Data_Transfer[15],0,8)BTD(R95C.Write.SMR.P2_D2_Reset_Count,24,Port_Data.Data_Transfer[16],0,8)BTD(R95C.Write.SMR.P2_D2_Reset_Count,16,Port_Data.Data_Transfer[17],0,8)BTD(R95C.Write.SMR.P2_D2_Reset_Count,8,Port_Data.Data_Transfer[18],0,8)BTD(R95C.Write.SMR.P2_D2_Reset_Count,0,Port_Data.Data_Transfer[19],0,8)BTD(R95C.Write.SMR.P2_D1_Reset_Count,24,Port_Data.Data_Transfer[20],0,8)BTD(R95C.Write.SMR.P2_D1_Reset_Count,16,Port_Data.Data_Transfer[21],0,8)BTD(R95C.Write.SMR.P2_D1_Reset_Count,8,Port_Data.Data_Transfer[22],0,8)BTD(R95C.Write.SMR.P2_D1_Reset_Count,0,Port_Data.Data_Transfer[23],0,8)BTD(R95C.Write.SMR.P1_D2_Reset_Count,24,Port_Data.Data_Transfer[24],0,8)BTD(R95C.Write.SMR.P1_D2_Reset_Count,16,Port_Data.Data_Transfer[25],0,8)BTD(R95C.Write.SMR.P1_D2_Reset_Count,8,Port_Data.Data_Transfer[26],0,8)BTD(R95C.Write.SMR.P1_D2_Reset_Count,0,Port_Data.Data_Transfer[27],0,8)BTD(R95C.Write.SMR.P1_D1_Reset_Count,24,Port_Data.Data_Transfer[28],0,8)BTD(R95C.Write.SMR.P1_D1_Reset_Count,16,Port_Data.Data_Transfer[29],0,8)BTD(R95C.Write.SMR.P1_D1_Reset_Count,8,Port_Data.Data_Transfer[30],0,8)BTD(R95C.Write.SMR.P1_D1_Reset_Count,0,Port_Data.Data_Transfer[31],0,8)BTD(R95C.Write.SMR.P1_Discrete1,0,Port_Data.Data_Transfer[32],0,1)BTD(R95C.Write.SMR.P1_Discrete2,0,Port_Data.Data_Transfer[32],1,1)BTD(R95C.Write.SMR.P2_Discrete1,0,Port_Data.Data_Transfer[32],2,1)BTD(R95C.Write.SMR.P2_Discrete2,0,Port_Data.Data_Transfer[32],3,1)BTD(R95C.Write.SMR.P3_Discrete1,0,Port_Data.Data_Transfer[32],4,1)BTD(R95C.Write.SMR.P3_Discrete2,0,Port_Data.Data_Transfer[32],5,1)BTD(R95C.Write.SMR.P4_Discrete1,0,Port_Data.Data_Transfer[32],6,1)BTD(R95C.Write.SMR.P4_Discrete2,0,Port_Data.Data_Transfer[32],7,1)MOV(Port,Port_Data.Data_Transfer[185])MOV(0,Port_Data.Data_Transfer[187])MOV(82,Port_Data.Data_Transfer[188])MOV(33,Port_Data.Data_Transfer[189])MOV(10,Inprocess_Index)OTL(Port_Data.Port_Write.[Port])OTL(Local_Control.11);
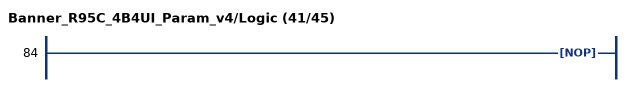
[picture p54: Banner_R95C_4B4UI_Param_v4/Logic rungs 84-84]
   84: NOP();
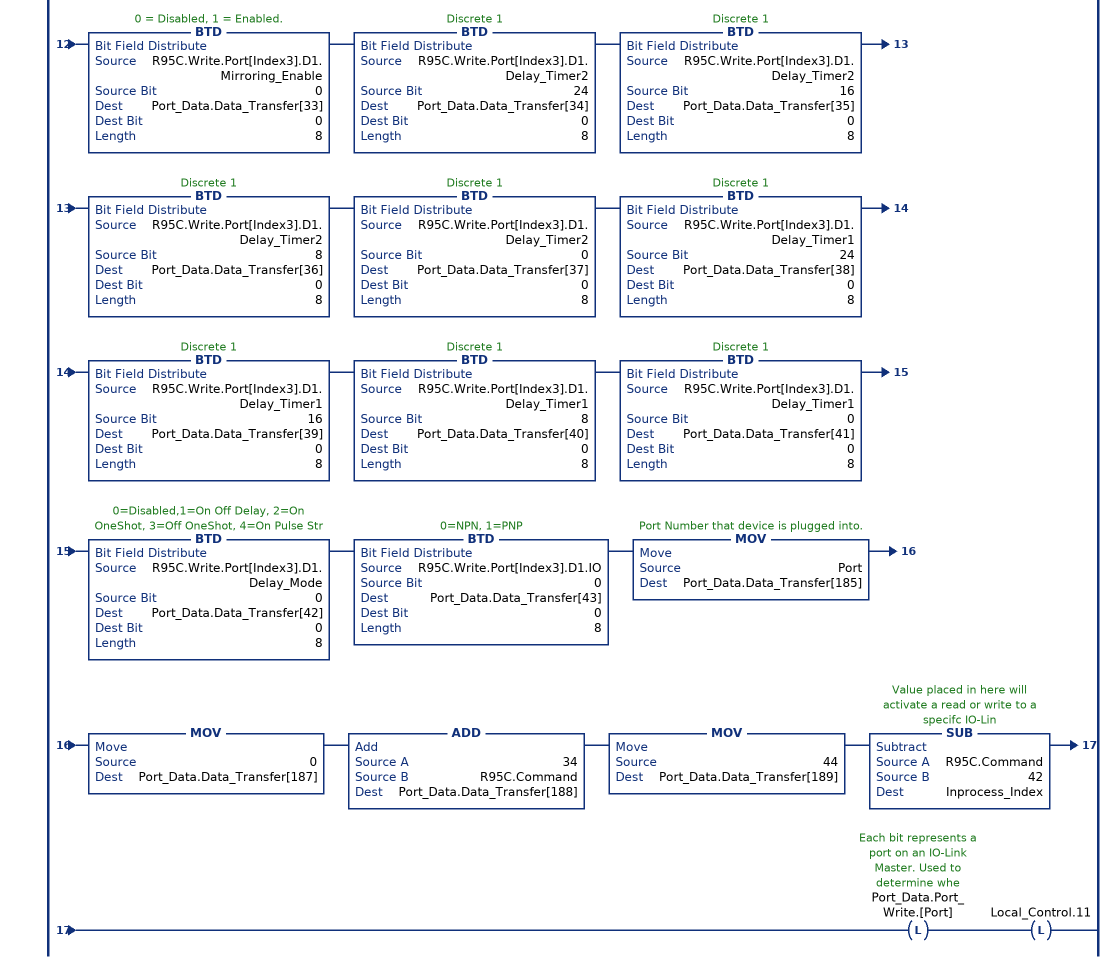
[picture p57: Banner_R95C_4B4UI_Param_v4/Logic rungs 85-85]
   // ************************************************************************************************************
   // Section of AOI that controls writing of the Port Configuration 1 to 4 parameter (index 87 to 90).
   // ************************************************************************************************************
   85: XIO(Command_Being_Processed)XIO(Local_Control.11)GEQ(R95C.Command,53)LEQ(R95C.Command,56)OTL(Command_Being_Processed)SUB(R95C.Command,52,Index3)BTD(R95C.Write.Port[Index3].D2.PFM_Far_Freq,24,Port_Data.Data_Transfer[0],0,8)BTD(R95C.Write.Port[Index3].D2.PFM_Far_Freq,16,Port_Data.Data_Transfer[1],0,8)BTD(R95C.Write.Port[Index3].D2.PFM_Far_Freq,8,Port_Data.Data_Transfer[2],0,8)BTD(R95C.Write.Port[Index3].D2.PFM_Far_Freq,0,Port_Data.Data_Transfer[3],0,8)BTD(R95C.Write.Port[Index3].D2.PFM_Near_Freq,24,Port_Data.Data_Transfer[4],0,8)BTD(R95C.Write.Port[Index3].D2.PFM_Near_Freq,16,Port_Data.Data_Transfer[5],0,8)BTD(R95C.Write.Port[Index3].D2.PFM_Near_Freq,8,Port_Data.Data_Transfer[6],0,8)BTD(R95C.Write.Port[Index3].D2.PFM_Near_Freq,0,Port_Data.Data_Transfer[7],0,8)BTD(R95C.Write.Port[Index3].D2.Mirroring_Inversion,0,Port_Data.Data_Transfer[8],0,8)BTD(R95C.Write.Port[Index3].D2.Mirroring_Channel_Selection,0,Port_Data.Data_Transfer[9],0,8)BTD(R95C.Write.Port[Index3].D2.Mirroring_Port_Selection,0,Port_Data.Data_Transfer[10],0,8)BTD(R95C.Write.Port[Index3].D2.Mirroring_Enable,0,Port_Data.Data_Transfer[11],0,8)BTD(R95C.Write.Port[Index3].D2.Delay_Timer2,24,Port_Data.Data_Transfer[12],0,8)BTD(R95C.Write.Port[Index3].D2.Delay_Timer2,16,Port_Data.Data_Transfer[13],0,8)BTD(R95C.Write.Port[Index3].D2.Delay_Timer2,8,Port_Data.Data_Transfer[14],0,8)BTD(R95C.Write.Port[Index3].D2.Delay_Timer2,0,Port_Data.Data_Transfer[15],0,8)BTD(R95C.Write.Port[Index3].D2.Delay_Timer1,24,Port_Data.Data_Transfer[16],0,8)BTD(R95C.Write.Port[Index3].D2.Delay_Timer1,16,Port_Data.Data_Transfer[17],0,8)BTD(R95C.Write.Port[Index3].D2.Delay_Timer1,8,Port_Data.Data_Transfer[18],0,8)BTD(R95C.Write.Port[Index3].D2.Delay_Timer1,0,Port_Data.Data_Transfer[19],0,8)BTD(R95C.Write.Port[Index3].D2.Delay_Mode,0,Port_Data.Data_Transfer[20],0,8)BTD(R95C.Write.Port[Index3].D2.IO,0,Port_Data.Data_Transfer[21],0,8)BTD(R95C.Write.Port[Index3].D1.PFM_Far_Freq,24,Port_Data.Data_Transfer[22],0,8)BTD(R95C.Write.Port[Index3].D1.PFM_Far_Freq,16,Port_Data.Data_Transfer[23],0,8)BTD(R95C.Write.Port[Index3].D1.PFM_Far_Freq,8,Port_Data.Data_Transfer[24],0,8)BTD(R95C.Write.Port[Index3].D1.PFM_Far_Freq,0,Port_Data.Data_Transfer[25],0,8)BTD(R95C.Write.Port[Index3].D1.PFM_Near_Freq,24,Port_Data.Data_Transfer[26],0,8)BTD(R95C.Write.Port[Index3].D1.PFM_Near_Freq,16,Port_Data.Data_Transfer[27],0,8)BTD(R95C.Write.Port[Index3].D1.PFM_Near_Freq,8,Port_Data.Data_Transfer[28],0,8)BTD(R95C.Write.Port[Index3].D1.PFM_Near_Freq,0,Port_Data.Data_Transfer[29],0,8)BTD(R95C.Write.Port[Index3].D1.Mirroring_Inversion,0,Port_Data.Data_Transfer[30],0,8)BTD(R95C.Write.Port[Index3].D1.Mirroring_Channel_Selection,0,Port_Data.Data_Transfer[31],0,8)BTD(R95C.Write.Port[Index3].D1.Mirroring_Port_Selection,0,Port_Data.Data_Transfer[32],0,8)BTD(R95C.Write.Port[Index3].D1.Mirroring_Enable,0,Port_Data.Data_Transfer[33],0,8)BTD(R95C.Write.Port[Index3].D1.Delay_Timer2,24,Port_Data.Data_Transfer[34],0,8)BTD(R95C.Write.Port[Index3].D1.Delay_Timer2,16,Port_Data.Data_Transfer[35],0,8)BTD(R95C.Write.Port[Index3].D1.Delay_Timer2,8,Port_Data.Data_Transfer[36],0,8)BTD(R95C.Write.Port[Index3].D1.Delay_Timer2,0,Port_Data.Data_Transfer[37],0,8)BTD(R95C.Write.Port[Index3].D1.Delay_Timer1,24,Port_Data.Data_Transfer[38],0,8)BTD(R95C.Write.Port[Index3].D1.Delay_Timer1,16,Port_Data.Data_Transfer[39],0,8)BTD(R95C.Write.Port[Index3].D1.Delay_Timer1,8,Port_Data.Data_Transfer[40],0,8)BTD(R95C.Write.Port[Index3].D1.Delay_Timer1,0,Port_Data.Data_Transfer[41],0,8)BTD(R95C.Write.Port[Index3].D1.Delay_Mode,0,Port_Data.Data_Transfer[42],0,8)BTD(R95C.Write.Port[Index3].D1.IO,0,Port_Data.Data_Transfer[43],0,8)MOV(Port,Port_Data.Data_Transfer[185])MOV(0,Port_Data.Data_Transfer[187])ADD(34,R95C.Command,Port_Data.Data_Transfer[188])MOV(44,Port_Data.Data_Transfer[189])SUB(R95C.Command,42,Inprocess_Index)OTL(Port_Data.Port_Write.[Port])OTL(Local_Control.11);
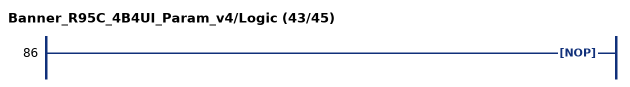
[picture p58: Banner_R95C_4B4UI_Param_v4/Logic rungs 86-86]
   86: NOP();
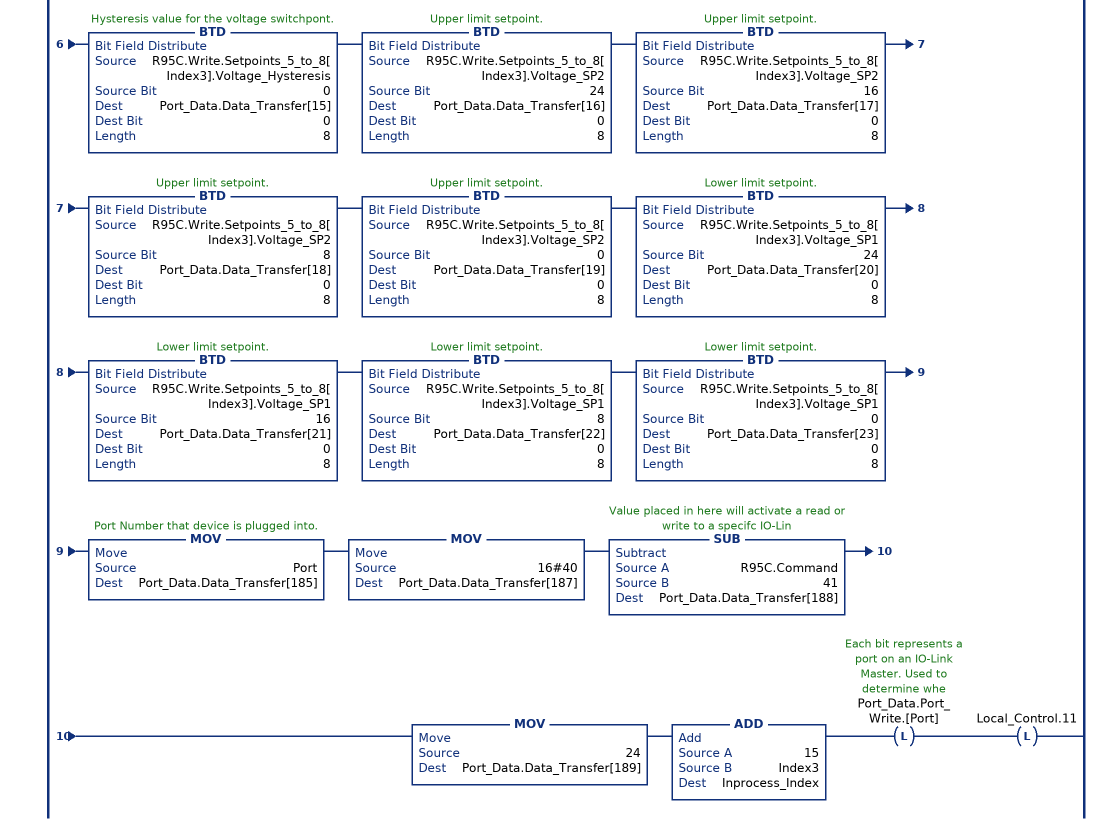
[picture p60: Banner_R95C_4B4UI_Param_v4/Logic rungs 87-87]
   // ************************************************************************************************************
   // Section of AOI that controls writing of the Channel 5 to 8 Setpoints Parameters (index 91 to Index 94).
   // ************************************************************************************************************
   87: XIO(Command_Being_Processed)XIO(Local_Control.11)GEQ(R95C.Command,57)LEQ(R95C.Command,60)SUB(R95C.Command,57,Index3)OTL(Command_Being_Processed)BTD(R95C.Write.Setpoints_5_to_8[Index3].Current_Hysteresis,24,Port_Data.Data_Transfer[0],0,8)BTD(R95C.Write.Setpoints_5_to_8[Index3].Current_Hysteresis,16,Port_Data.Data_Transfer[1],0,8)BTD(R95C.Write.Setpoints_5_to_8[Index3].Current_Hysteresis,8,Port_Data.Data_Transfer[2],0,8)BTD(R95C.Write.Setpoints_5_to_8[Index3].Current_Hysteresis,0,Port_Data.Data_Transfer[3],0,8)BTD(R95C.Write.Setpoints_5_to_8[Index3].Current_SP2,24,Port_Data.Data_Transfer[4],0,8)BTD(R95C.Write.Setpoints_5_to_8[Index3].Current_SP2,16,Port_Data.Data_Transfer[5],0,8)BTD(R95C.Write.Setpoints_5_to_8[Index3].Current_SP2,8,Port_Data.Data_Transfer[6],0,8)BTD(R95C.Write.Setpoints_5_to_8[Index3].Current_SP2,0,Port_Data.Data_Transfer[7],0,8)BTD(R95C.Write.Setpoints_5_to_8[Index3].Current_SP1,24,Port_Data.Data_Transfer[8],0,8)BTD(R95C.Write.Setpoints_5_to_8[Index3].Current_SP1,16,Port_Data.Data_Transfer[9],0,8)BTD(R95C.Write.Setpoints_5_to_8[Index3].Current_SP1,8,Port_Data.Data_Transfer[10],0,8)BTD(R95C.Write.Setpoints_5_to_8[Index3].Current_SP1,0,Port_Data.Data_Transfer[11],0,8)BTD(R95C.Write.Setpoints_5_to_8[Index3].Voltage_Hysteresis,24,Port_Data.Data_Transfer[12],0,8)BTD(R95C.Write.Setpoints_5_to_8[Index3].Voltage_Hysteresis,16,Port_Data.Data_Transfer[13],0,8)BTD(R95C.Write.Setpoints_5_to_8[Index3].Voltage_Hysteresis,8,Port_Data.Data_Transfer[14],0,8)BTD(R95C.Write.Setpoints_5_to_8[Index3].Voltage_Hysteresis,0,Port_Data.Data_Transfer[15],0,8)BTD(R95C.Write.Setpoints_5_to_8[Index3].Voltage_SP2,24,Port_Data.Data_Transfer[16],0,8)BTD(R95C.Write.Setpoints_5_to_8[Index3].Voltage_SP2,16,Port_Data.Data_Transfer[17],0,8)BTD(R95C.Write.Setpoints_5_to_8[Index3].Voltage_SP2,8,Port_Data.Data_Transfer[18],0,8)BTD(R95C.Write.Setpoints_5_to_8[Index3].Voltage_SP2,0,Port_Data.Data_Transfer[19],0,8)BTD(R95C.Write.Setpoints_5_to_8[Index3].Voltage_SP1,24,Port_Data.Data_Transfer[20],0,8)BTD(R95C.Write.Setpoints_5_to_8[Index3].Voltage_SP1,16,Port_Data.Data_Transfer[21],0,8)BTD(R95C.Write.Setpoints_5_to_8[Index3].Voltage_SP1,8,Port_Data.Data_Transfer[22],0,8)BTD(R95C.Write.Setpoints_5_to_8[Index3].Voltage_SP1,0,Port_Data.Data_Transfer[23],0,8)MOV(Port,Port_Data.Data_Transfer[185])MOV(16#40,Port_Data.Data_Transfer[187])SUB(R95C.Command,41,Port_Data.Data_Transfer[188])MOV(24,Port_Data.Data_Transfer[189])ADD(15,Index3,Inprocess_Index)OTL(Port_Data.Port_Write.[Port])OTL(Local_Control.11);
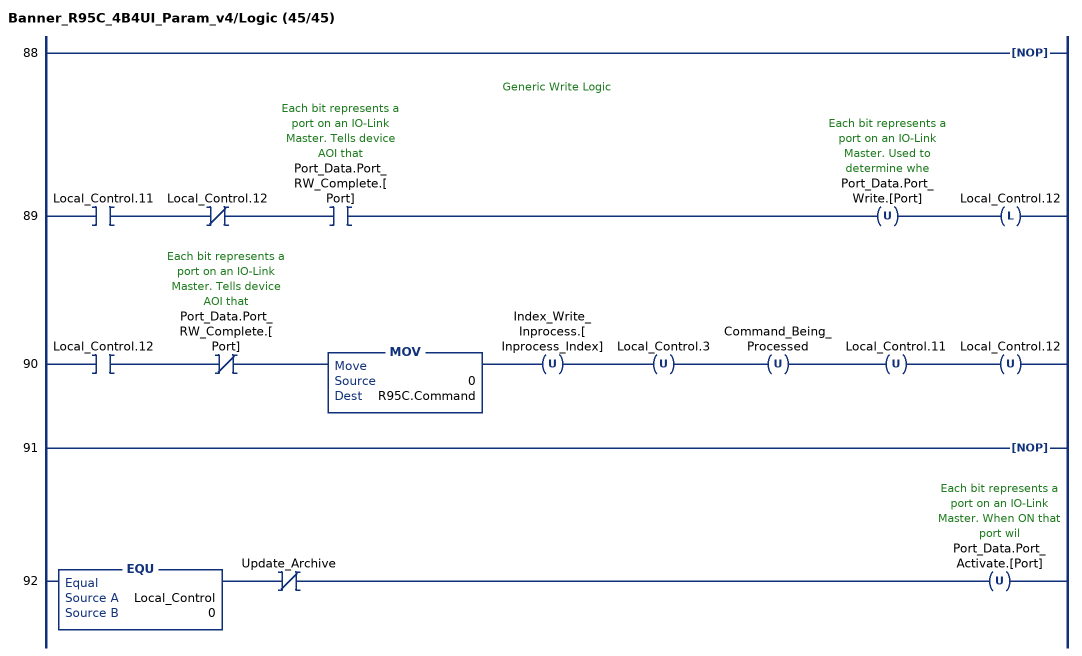
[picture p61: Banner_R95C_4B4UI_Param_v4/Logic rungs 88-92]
   88: NOP();
   // Generic Write Logic
   89: XIC(Local_Control.11)XIO(Local_Control.12)XIC(Port_Data.Port_RW_Complete.[Port])OTU(Port_Data.Port_Write.[Port])OTL(Local_Control.12);
   90: XIC(Local_Control.12)XIO(Port_Data.Port_RW_Complete.[Port])MOV(0,R95C.Command)OTU(Index_Write_Inprocess.[Inprocess_Index])OTU(Local_Control.3)OTU(Command_Being_Processed)OTU(Local_Control.11)OTU(Local_Control.12);
   91: NOP();
   92: EQU(Local_Control,0)XIO(Update_Archive)OTU(Port_Data.Port_Activate.[Port]);
END_ROUTINE
END_ADD_ON_INSTRUCTION
